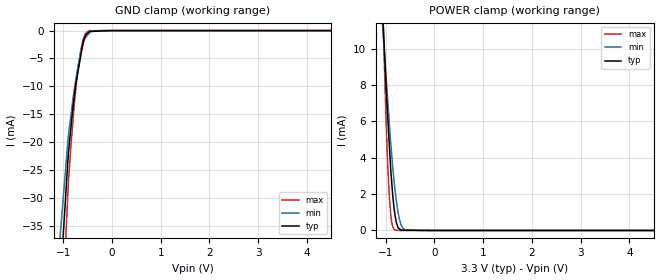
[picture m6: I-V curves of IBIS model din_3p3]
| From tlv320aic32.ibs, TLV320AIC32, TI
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|   din_3p3 Model
[Model]   din_3p3
Model_type   Input
Vinl = 0.99
Vinh = 2.31
|   typ   min   max
|   (nom PVT)   (fast PVT)   (slow PVT)
|C_comp from frequency sweep method (F=25MHz)
|Average
|Average
|C_comp   6.612e-12   6.429e-12   6.796e-12
|C_comp from LC tank measurement(L=1nH)
|Average
|Resonant Frequency(Hz)   2.150e+09   2.170e+09   2.140e+09
C_comp   5.485e-12   5.385e-12   5.537e-12
| Where nom  PVT is Nominal Process, 3.3V, 26C
|   Fast PVT is Strong Process,  3.6V, -40C
|   Slow PVT is Weak Process,   3V, 86C
[Model Spec]
|Subparameter   typ   min   max
Vinl   0.99   0.9   1.08
Vinh   2.31   2.1   2.52
[Voltage Range]   3.3   3   3.6
|Ambient Temperature   25   85   -40
|Junction Temperature
[Temperature Range]   26   86   -40
[Power Clamp Reference]   3.3   3   3.6
[GND Clamp Reference]   0   0   0
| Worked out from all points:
|   GND clamp passes 1 mA (typ) near -0.55 V on its own axis
|   POWER clamp passes 1 mA (typ) near -0.82 V on its own axis
[GND Clamp]
|   Voltage   I(typ)   I(min)   I(max)
-3.3V     -1.384A    -1.199A    -1.638A
-1.451V   -99.45mA   -78.32mA   -132.3mA
-897.6mV  -22.27mA   -18.95mA   -27.54mA
-842.4mV  -17.31mA   -15.11mA   -20.63mA
-792mV    -13.07mA   -11.62mA   -15.13mA
-745.8mV  -9.711mA   -8.96mA    -10.77mA
-691.2mV  -7.004mA   -6.098mA   -6.475mA
-601.2mV  -2.542mA   -2.645mA   -1.857mA
-554.4mV  -1.128mA   -1.419mA   -707.6uA
-500.4mV  -468.1uA   -819.4uA   -172.4uA
-285mV    -101.7uA   -3.563uA   -12.71uA
6.6V      0A         0A         0A
[POWER Clamp]
|   Voltage   I(typ)   I(min)   I(max)
-3.3V     157.9mA    110.4mA    274.6mA
-1.089V   13.36mA    12.1mA     15.18mA
-1.037V   10.41mA    10.1mA     9.822mA
-993.6mV  7.977mA    8.451mA    6.026mA
-961.2mV  6.3mA      7.213mA    3.694mA
-928.8mV  4.786mA    5.974mA    1.956mA
-874.8mV  2.533mA    4.048mA    387.6uA
-820.8mV  1.031mA    2.477mA    39.19uA
-785.4mV  455.6uA    1.675mA    15.66uA
-717mV    84.01uA    584.6uA    1.359uA
-591mV    14.18uA    23.34uA    0A
6.6V      0A         0A         0A
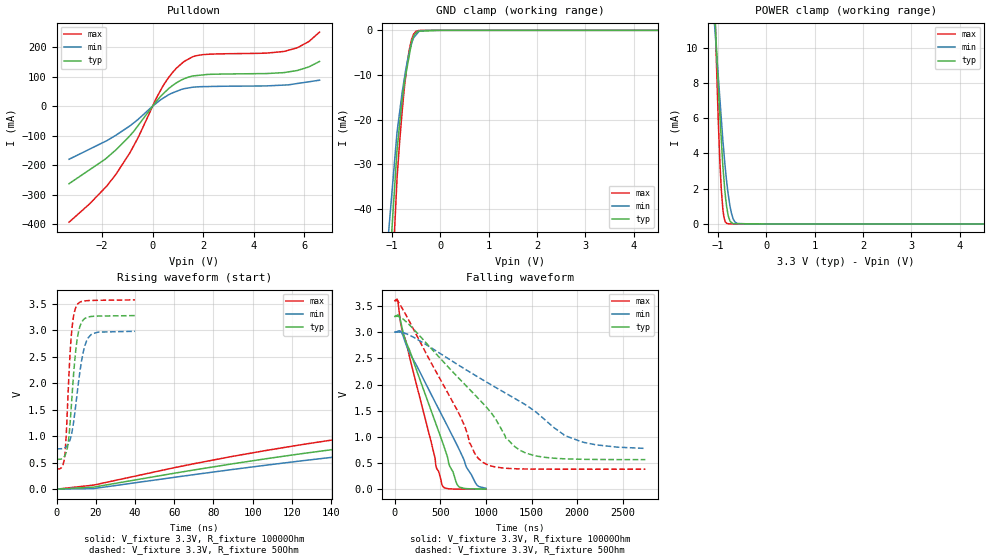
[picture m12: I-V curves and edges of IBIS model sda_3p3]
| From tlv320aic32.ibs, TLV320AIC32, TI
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|   sda_3p3 Model
[Model]   sda_3p3
Model_type   Open_drain
Polarity   Inverting
Vmeas = 1.65
Vref = 3.3
Cref = 10pF
Rref = 10000
|   typ   min   max
|   (nom PVT)   (fast PVT)   (slow PVT)
|C_comp from frequency sweep method (F=400KHz)
|C_comp   2.273e-11   2.209e-11   2.278e-11
|ON state : BUFFER OUTPUT TURNED LOW
|C_comp   4.891e-09   3.775e-09   6.125e-09
|OFF state: BUFFER IN HIGH IMPEDANCE
|C_comp   2.273e-11   2.209e-11   2.278e-11
|C_comp from LC tank measurement(L=1nH)
|Resonant Frequency(Hz)   1.960e+09   1.980e+09   1.950e+09
C_comp   6.600e-12   6.468e-12   6.668e-12
|ON state : BUFFER OUTPUT TURNED LOW
|Resonant Frequency(Hz)   1.960e+09   1.980e+09   1.950e+09
|C_comp   6.600e-12   6.468e-12   6.668e-12
|OFF state: BUFFER IN HIGH IMPEDANCE
|Resonant Frequency(Hz)   2.110e+09   2.120e+09   2.090e+09
|C_comp   5.695e-12   5.642e-12   5.805e-12
| Where nom  PVT is Nominal Process, 3.3V, 26C
|   Fast PVT is Strong Process,  3.6V, -40C
|   Slow PVT is Weak Process,   3V, 86C
[Voltage Range]   3.3   3   3.6
|Ambient Temperature   25   85   -40
|Junction Temperature
[Temperature Range]   26   86   -40
[Pullup Reference]   3.3   3   3.6
[Pulldown Reference]   0   0   0
[Power Clamp Reference]   3.3   3   3.6
[GND Clamp Reference]   0   0   0
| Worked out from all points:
|   slope of the pulldown table from 0 to 0.495 V, typ, clamps not added: 10.2 ohm
|   GND clamp passes 1 mA (typ) near -0.54 V on its own axis
|   POWER clamp passes 1 mA (typ) near -0.82 V on its own axis
|   falling waveform, V_fixture 3.3V, R_fixture 10000Ohm: 20-80 % time 405ns typ, 520ns min, 312ns max; typ from 3.3 V to 0.004 V
|   rising waveform, V_fixture 3.3V, R_fixture 10000Ohm: 20-80 % time 787ns typ, 867ns min, 704ns max; typ from 0.003 V to 3.29 V
|   falling waveform, V_fixture 3.3V, R_fixture 50Ohm: 20-80 % time 816ns typ, 1.19us min, 566ns max; typ from 3.3 V to 0.566 V
|   rising waveform, V_fixture 3.3V, R_fixture 50Ohm: 20-80 % time 3.56ns typ, 4.89ns min, 2.7ns max; typ from 0.565 V to 3.28 V
[Pulldown]
|   Voltage   I(typ)   I(min)   I(max)
-3.3V     -262.9mA   -180mA     -393.7mA
-2.48V    -215.2mA   -145.3mA   -330.8mA
-1.458V   -148.9mA   -99.06mA   -232.5mA
-583.2mV  -66.98mA   -45.49mA   -108.4mA
388.8mV   39.5mA     25.78mA    65.24mA
799.2mV   71mA       45.56mA    115.6mA
1.235V    92.81mA    59.3mA     151.2mA
1.958V    106.1mA    66.45mA    174.8mA
5.188V    114.1mA    71.79mA    185.9mA
5.72V     121.3mA    77.17mA    198.4mA
6.181V    133.6mA    83.06mA    219.8mA
6.6V      152.1mA    88.43mA    251.7mA
[GND Clamp]
|   Voltage   I(typ)   I(min)   I(max)
-3.3V     -1.344A    -1.13A     -1.633A
-1.447V   -119.4mA   -93.71mA   -159mA
-897.6mV  -26.97mA   -22.95mA   -33.38mA
-842.4mV  -20.97mA   -18.29mA   -25mA
-792mV    -15.83mA   -14.07mA   -18.33mA
-745.8mV  -11.76mA   -10.85mA   -13.05mA
-691.2mV  -8.484mA   -7.38mA    -7.845mA
-601.2mV  -3.078mA   -3.2mA     -2.248mA
-554.4mV  -1.366mA   -1.715mA   -856.1uA
-500.4mV  -566.1uA   -990.5uA   -208.2uA
-285mV    -122.8uA   -4.282uA   -15.3uA
6.6V      0A         0A         0A
[POWER Clamp]
|   Voltage   I(typ)   I(min)   I(max)
-3.3V     157.9mA    110.4mA    274.6mA
-1.089V   13.36mA    12.1mA     15.18mA
-1.037V   10.41mA    10.1mA     9.822mA
-993.6mV  7.977mA    8.451mA    6.026mA
-961.2mV  6.3mA      7.213mA    3.694mA
-928.8mV  4.786mA    5.974mA    1.956mA
-874.8mV  2.533mA    4.048mA    387.6uA
-820.8mV  1.031mA    2.477mA    39.19uA
-785.4mV  455.6uA    1.675mA    15.66uA
-717mV    84.01uA    584.6uA    1.359uA
-591mV    14.18uA    23.34uA    10.03nA
6.6V      0A         0A         0A
[Ramp]
R_load = 10000
|   typ   min   max
dV/dt_r   1.9694/7.86619e-07   1.78292/8.66448e-07   2.15419/7.03792e-07
dV/dt_f   1.97831/4.03063e-07   1.79765/5.25658e-07   2.15888/3.13369e-07
[Falling Waveform]
V_fixture = 3.3V
V_fixture_min = 3V
V_fixture_max = 3.6V
R_fixture = 10000Ohm
|   Time   V(typ)   V(min)   V(max)
0s        3.3V       3V         3.6V
29.7ns    3.327V     3.015V     3.61V
49.6ns    3.295V     3.026V     3.352V
75.74ns   3.107V     2.986V     3.061V
110.2ns   2.867V     2.827V     2.884V
453.6ns   1.234V     1.624V     423.3mV
523.5ns   895.5mV    1.388V     61.07mV
704.8ns   44.39mV    763.5mV    3.186mV
884.4ns   5.669mV    121.9mV    2.128mV
1us       3.94mV     19.23mV    1.98mV
[Rising Waveform]
V_fixture = 3.3V
V_fixture_min = 3V
V_fixture_max = 3.6V
R_fixture = 10000Ohm
|   Time   V(typ)   V(min)   V(max)
0s        2.821mV    3.916mV    1.873mV
18.85ns   40.17mV    12.73mV    78.28mV
89.64ns   480.3mV    373.4mV    620.9mV
169.9ns   886.7mV    723.7mV    1.09V
366ns     1.601V     1.351V     1.896V
612.8ns   2.188V     1.876V     2.538V
913.6ns   2.634V     2.288V     3.009V
1.244us   2.924V     2.57V      3.292V
1.732us   3.139V     2.797V     3.483V
3.1us     3.285V     2.975V     3.592V
[Falling Waveform]
V_fixture = 3.3V
V_fixture_min = 3V
V_fixture_max = 3.6V
R_fixture = 50Ohm
|   Time   V(typ)   V(min)   V(max)
0s        3.3V       3V         3.6V
133.6ns   3.183V     2.963V     3.289V
679.2ns   2.161V     2.391V     1.526V
872.3ns   1.812V     2.185V     699.9mV
967.5ns   1.637V     2.086V     511.9mV
1.215us   982.3mV    1.835V     402mV
1.441us   689.7mV    1.606V     386.7mV
1.864us   581.3mV    1.019V     382.8mV
2.211us   568.7mV    847.5mV    382.6mV
2.75us    565.8mV    779.9mV    382.6mV
[Rising Waveform]
V_fixture = 3.3V
V_fixture_min = 3V
V_fixture_max = 3.6V
R_fixture = 50Ohm
|   Time   V(typ)   V(min)   V(max)
0s        565.5mV    765.2mV    382.6mV
4.05ns    623.1mV    781.1mV    583.3mV
4.925ns   695.1mV    804.9mV    1.014V
6.005ns   888.1mV    858.7mV    1.898V
7.415ns   1.503V     1.003V     2.847V
8.565ns   2.108V     1.234V     3.241V
10.08ns   2.712V     1.675V     3.456V
12.91ns   3.161V     2.457V     3.548V
16.27ns   3.254V     2.866V     3.563V
40ns      3.28V      2.983V     3.576V
